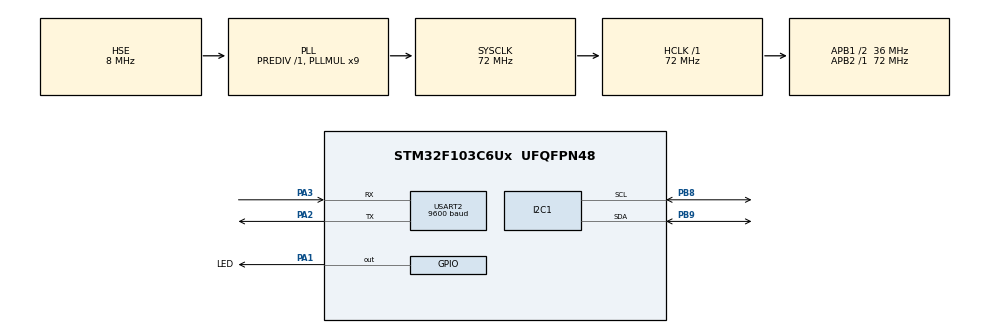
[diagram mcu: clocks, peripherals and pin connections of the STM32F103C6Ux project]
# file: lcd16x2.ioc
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Mcu.Family=STM32F1
Mcu.Name=STM32F103C6Ux
Mcu.Package=UFQFPN48
NVIC.PriorityGroup=NVIC_PRIORITYGROUP_4
NVIC.TIM2_IRQn=true\:0\:0\:false\:false\:true\:true\:true\:true
PA1.GPIO_Label=LED
PA1.Signal=GPIO_Output
PA13.Mode=Serial_Wire
PA13.Signal=SYS_JTMS-SWDIO
PA14.Mode=Serial_Wire
PA14.Signal=SYS_JTCK-SWCLK
PA2.Mode=Asynchronous
PA2.Signal=USART2_TX
PA3.Mode=Asynchronous
PA3.Signal=USART2_RX
PB8.GPIO_Pu=GPIO_PULLUP
PB8.Mode=I2C
PB8.Signal=I2C1_SCL
PB9.GPIO_Pu=GPIO_PULLUP
PB9.Mode=I2C
PB9.Signal=I2C1_SDA
PD0-OSC_IN.Mode=HSE-External-Oscillator
PD0-OSC_IN.Signal=RCC_OSC_IN
PD1-OSC_OUT.Mode=HSE-External-Oscillator
PD1-OSC_OUT.Signal=RCC_OSC_OUT
ProjectManager.HeapSize=0x200
ProjectManager.StackSize=0x400
ProjectManager.TargetToolchain=STM32CubeIDE
RCC.AHBFreq_Value=72000000
RCC.APB1CLKDivider=RCC_HCLK_DIV2
RCC.APB1Freq_Value=36000000
RCC.APB1TimFreq_Value=72000000
RCC.APB2Freq_Value=72000000
RCC.APB2TimFreq_Value=72000000
RCC.HCLKFreq_Value=72000000
RCC.PLLMUL=RCC_PLL_MUL9
RCC.PLLSourceVirtual=RCC_PLLSOURCE_HSE
RCC.SYSCLKFreq_VALUE=72000000
RCC.SYSCLKSource=RCC_SYSCLKSOURCE_PLLCLK
RCC.USBFreq_Value=72000000
TIM2.AutoReloadPreload=TIM_AUTORELOAD_PRELOAD_ENABLE
TIM2.Period=99
TIM2.Prescaler=7199
USART2.BaudRate=9600
USART2.VirtualMode=VM_ASYNC
VP_TIM2_VS_ClockSourceINT.Mode=Internal
board=custom

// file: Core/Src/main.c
/* USER CODE BEGIN Header */
/**
  ******************************************************************************
  * @file           : main.c
  * @brief          : Main program body
  ******************************************************************************
  * @attention
  *
  * <h2><center>&copy; Copyright (c) 2022 STMicroelectronics.
  * All rights reserved.</center></h2>
  *
  * This software component is licensed by ST under BSD 3-Clause license,
  * the "License"; You may not use this file except in compliance with the
  * License. You may obtain a copy of the License at:
  *                        opensource.org/licenses/BSD-3-Clause
  *
  ******************************************************************************
  */
/* USER CODE END Header */
#include "main.h"

/* USER CODE BEGIN Includes */
#include "pcf8574_new.h"
#include "button.h"
#include "software_timer.h"
#include "global.h"
#include "fsm_automatic.h"
#include "fsm_manual.h"
#include "scheduler.h"
#include "i2c-lcd_2.h"
#include <stdio.h>

/* USER CODE END Includes */

/* USER CODE BEGIN PD */
#include <string.h>

#define LCD_ADDR (0x27 << 1)
#define LCD_DELAY_MS 5
#define PIN_RS    (1 << 0)
#define PIN_EN    (1 << 2)
#define BACKLIGHT (1 << 3)
/* USER CODE END PD */

I2C_HandleTypeDef hi2c1;

TIM_HandleTypeDef htim2;

UART_HandleTypeDef huart2;

void SystemClock_Config(void);
static void MX_GPIO_Init(void);
static void MX_TIM2_Init(void);
static void MX_USART2_UART_Init(void);
static void MX_I2C1_Init(void);

/* USER CODE BEGIN 0 */
void led1test(){
	HAL_GPIO_TogglePin(LED3_00_GPIO_Port, LED3_00_Pin);
}
void I2C_Scan() {
    char info[] = "Scanning I2C bus...\r\n";
    HAL_UART_Transmit(&huart2, (uint8_t*)info, strlen(info), HAL_MAX_DELAY);

    HAL_StatusTypeDef res;
    for(uint16_t i = 0; i < 128; i++) {
        res = HAL_I2C_IsDeviceReady(&hi2c1, i << 1, 3, 5);
        if(res == HAL_OK) {
            char msg[64];
            snprintf(msg, sizeof(msg), "0x%02X", i);
            HAL_UART_Transmit(&huart2, (uint8_t*)msg, strlen(msg), HAL_MAX_DELAY);
        } else {
            HAL_UART_Transmit(&huart2, (uint8_t*)".", 1, HAL_MAX_DELAY);
        }
    }

    HAL_UART_Transmit(&huart2, (uint8_t*)"\r\n", 2, HAL_MAX_DELAY);
}

HAL_StatusTypeDef LCD_SendInternal(uint8_t lcd_addr, uint8_t data, uint8_t flags) {
    HAL_StatusTypeDef res;
    for(;;) {
        res = HAL_I2C_IsDeviceReady(&hi2c1, lcd_addr, 1, HAL_MAX_DELAY);
        if(res == HAL_OK)
            break;
    }

    uint8_t up = data & 0xF0;
    uint8_t lo = (data << 4) & 0xF0;

    uint8_t data_arr[4];
    data_arr[0] = up|flags|BACKLIGHT|PIN_EN;
    data_arr[1] = up|flags|BACKLIGHT;
    data_arr[2] = lo|flags|BACKLIGHT|PIN_EN;
    data_arr[3] = lo|flags|BACKLIGHT;

    res = HAL_I2C_Master_Transmit(&hi2c1, lcd_addr, data_arr, sizeof(data_arr), HAL_MAX_DELAY);
    HAL_Delay(LCD_DELAY_MS);
    return res;
}

void LCD_SendCommand(uint8_t lcd_addr, uint8_t cmd) {
    LCD_SendInternal(lcd_addr, cmd, 0);
}

void LCD_SendData(uint8_t lcd_addr, uint8_t data) {
    LCD_SendInternal(lcd_addr, data, PIN_RS);
}

void LCD_Init(uint8_t lcd_addr) {
    // 4-bit mode, 2 lines, 5x7 format
    LCD_SendCommand(lcd_addr, 0b00110000);
    // display & cursor home (keep this!)
    LCD_SendCommand(lcd_addr, 0b00000010);
    // display on, right shift, underline off, blink off
    LCD_SendCommand(lcd_addr, 0b00001100);
    // clear display (optional here)
    LCD_SendCommand(lcd_addr, 0b00000001);
}

void LCD_SendString(uint8_t lcd_addr, char *str) {
    while(*str) {
        LCD_SendData(lcd_addr, (uint8_t)(*str));
        str++;
    }
}

void init() {
    //I2C_Scan();
    LCD_Init(LCD_ADDR);

    // set address to 0x00
    LCD_SendCommand(LCD_ADDR, 0b10000000);
    LCD_SendString(LCD_ADDR, " Using 1602 LCD");

    // set address to 0x40
    LCD_SendCommand(LCD_ADDR, 0b11000000);
    LCD_SendString(LCD_ADDR, "  over I2C bus");
}

void loop() {
    HAL_Delay(100);
}
/* USER CODE END 0 */

int main(void)
{
  /* USER CODE BEGIN 1 */
	uint8_t Buffer[25] = {0};
	uint8_t Space[] = " - ";
	uint8_t StartMSG[] = "Starting I2C Scanning: \r\n";
	uint8_t EndMSG[] = "Done! \r\n\r\n";
  /* USER CODE END 1 */

  /* MCU Configuration--------------------------------------------------------*/

  /* Reset of all peripherals, Initializes the Flash interface and the Systick. */
  HAL_Init();

  /* Configure the system clock */
  SystemClock_Config();

  /* Initialize all configured peripherals */
  MX_GPIO_Init();
  MX_TIM2_Init();
  MX_USART2_UART_Init();
  MX_I2C1_Init();
  /* USER CODE BEGIN 2 */
  HAL_TIM_Base_Start_IT(&htim2);
  HAL_I2C_MspInit(&hi2c1);
  //

  /*-[ I2C Bus Scanning ]-*/

  //HAL_UART_Transmit(&huart2, (uint8_t *)&StartMSG,sizeof(StartMSG), 1000);
  HAL_Delay(1000);
  I2C_Scan();
  HAL_StatusTypeDef result;
  /*-[ I2C Bus Scanning ]-*/
  /* USER CODE END 2 */

  /* Infinite loop */
  /* USER CODE BEGIN WHILE */
  lcd_init();
  HAL_Delay(50);
  lcd_goto_XY(1, 4);
  lcd_send_string("hello dm");
  while(1){

  }
    /* USER CODE END WHILE */

}

void SystemClock_Config(void)
{
  RCC_OscInitTypeDef RCC_OscInitStruct = {0};
  RCC_ClkInitTypeDef RCC_ClkInitStruct = {0};

  /** Initializes the RCC Oscillators according to the specified parameters
  * in the RCC_OscInitTypeDef structure.
  */
  RCC_OscInitStruct.OscillatorType = RCC_OSCILLATORTYPE_HSE;
  RCC_OscInitStruct.HSEState = RCC_HSE_ON;
  RCC_OscInitStruct.HSEPredivValue = RCC_HSE_PREDIV_DIV1;
  RCC_OscInitStruct.HSIState = RCC_HSI_ON;
  RCC_OscInitStruct.PLL.PLLState = RCC_PLL_ON;
  RCC_OscInitStruct.PLL.PLLSource = RCC_PLLSOURCE_HSE;
  RCC_OscInitStruct.PLL.PLLMUL = RCC_PLL_MUL9;
  if (HAL_RCC_OscConfig(&RCC_OscInitStruct) != HAL_OK)
  {
    Error_Handler();
  }

  /** Initializes the CPU, AHB and APB buses clocks
  */
  RCC_ClkInitStruct.ClockType = RCC_CLOCKTYPE_HCLK|RCC_CLOCKTYPE_SYSCLK
                              |RCC_CLOCKTYPE_PCLK1|RCC_CLOCKTYPE_PCLK2;
  RCC_ClkInitStruct.SYSCLKSource = RCC_SYSCLKSOURCE_PLLCLK;
  RCC_ClkInitStruct.AHBCLKDivider = RCC_SYSCLK_DIV1;
  RCC_ClkInitStruct.APB1CLKDivider = RCC_HCLK_DIV2;
  RCC_ClkInitStruct.APB2CLKDivider = RCC_HCLK_DIV1;

  if (HAL_RCC_ClockConfig(&RCC_ClkInitStruct, FLASH_LATENCY_2) != HAL_OK)
  {
    Error_Handler();
  }
}

static void MX_I2C1_Init(void)
{

  hi2c1.Instance = I2C1;
  hi2c1.Init.ClockSpeed = 100000;
  hi2c1.Init.DutyCycle = I2C_DUTYCYCLE_2;
  hi2c1.Init.OwnAddress1 = 0;
  hi2c1.Init.AddressingMode = I2C_ADDRESSINGMODE_7BIT;
  hi2c1.Init.DualAddressMode = I2C_DUALADDRESS_DISABLE;
  hi2c1.Init.OwnAddress2 = 0;
  hi2c1.Init.GeneralCallMode = I2C_GENERALCALL_DISABLE;
  hi2c1.Init.NoStretchMode = I2C_NOSTRETCH_DISABLE;
  if (HAL_I2C_Init(&hi2c1) != HAL_OK)
  {
    Error_Handler();
  }

}

static void MX_TIM2_Init(void)
{

  TIM_ClockConfigTypeDef sClockSourceConfig = {0};
  TIM_MasterConfigTypeDef sMasterConfig = {0};

  htim2.Instance = TIM2;
  htim2.Init.Prescaler = 7999;
  htim2.Init.CounterMode = TIM_COUNTERMODE_UP;
  htim2.Init.Period = 9;
  htim2.Init.ClockDivision = TIM_CLOCKDIVISION_DIV1;
  htim2.Init.AutoReloadPreload = TIM_AUTORELOAD_PRELOAD_ENABLE;
  if (HAL_TIM_Base_Init(&htim2) != HAL_OK)
  {
    Error_Handler();
  }
  sClockSourceConfig.ClockSource = TIM_CLOCKSOURCE_INTERNAL;
  if (HAL_TIM_ConfigClockSource(&htim2, &sClockSourceConfig) != HAL_OK)
  {
    Error_Handler();
  }
  sMasterConfig.MasterOutputTrigger = TIM_TRGO_RESET;
  sMasterConfig.MasterSlaveMode = TIM_MASTERSLAVEMODE_DISABLE;
  if (HAL_TIMEx_MasterConfigSynchronization(&htim2, &sMasterConfig) != HAL_OK)
  {
    Error_Handler();
  }

}

static void MX_USART2_UART_Init(void)
{

  huart2.Instance = USART2;
  huart2.Init.BaudRate = 9600;
  huart2.Init.WordLength = UART_WORDLENGTH_8B;
  huart2.Init.StopBits = UART_STOPBITS_1;
  huart2.Init.Parity = UART_PARITY_NONE;
  huart2.Init.Mode = UART_MODE_TX_RX;
  huart2.Init.HwFlowCtl = UART_HWCONTROL_NONE;
  huart2.Init.OverSampling = UART_OVERSAMPLING_16;
  if (HAL_UART_Init(&huart2) != HAL_OK)
  {
    Error_Handler();
  }

}

static void MX_GPIO_Init(void)
{
  GPIO_InitTypeDef GPIO_InitStruct = {0};

  /* GPIO Ports Clock Enable */
  __HAL_RCC_GPIOD_CLK_ENABLE();
  __HAL_RCC_GPIOA_CLK_ENABLE();
  __HAL_RCC_GPIOB_CLK_ENABLE();

  /*Configure GPIO pin Output Level */
  HAL_GPIO_WritePin(GPIOA, LED3_10_Pin|LED3_11_Pin|LED_RED_Pin|LED3_00_Pin
                          |LED3_01_Pin, GPIO_PIN_RESET);

  /*Configure GPIO pins : LED3_10_Pin LED3_11_Pin LED_RED_Pin LED3_00_Pin
                           LED3_01_Pin */
  GPIO_InitStruct.Pin = LED3_10_Pin|LED3_11_Pin|LED_RED_Pin|LED3_00_Pin
                          |LED3_01_Pin;
  GPIO_InitStruct.Mode = GPIO_MODE_OUTPUT_PP;
  GPIO_InitStruct.Pull = GPIO_NOPULL;
  GPIO_InitStruct.Speed = GPIO_SPEED_FREQ_LOW;
  HAL_GPIO_Init(GPIOA, &GPIO_InitStruct);

  /*Configure GPIO pin : Button0_Pin */
  GPIO_InitStruct.Pin = Button0_Pin;
  GPIO_InitStruct.Mode = GPIO_MODE_INPUT;
  GPIO_InitStruct.Pull = GPIO_NOPULL;
  HAL_GPIO_Init(Button0_GPIO_Port, &GPIO_InitStruct);

  /*Configure GPIO pin : Button1_Pin */
  GPIO_InitStruct.Pin = Button1_Pin;
  GPIO_InitStruct.Mode = GPIO_MODE_INPUT;
  GPIO_InitStruct.Pull = GPIO_PULLUP;
  HAL_GPIO_Init(Button1_GPIO_Port, &GPIO_InitStruct);

}

/* USER CODE BEGIN 4 */

void HAL_TIM_PeriodElapsedCallback(TIM_HandleTypeDef *htim)
{
	timerRun();
	SCH_Update();
}
/* USER CODE END 4 */

void Error_Handler(void)
{
  __disable_irq();
  while (1)
  {
  }
}
